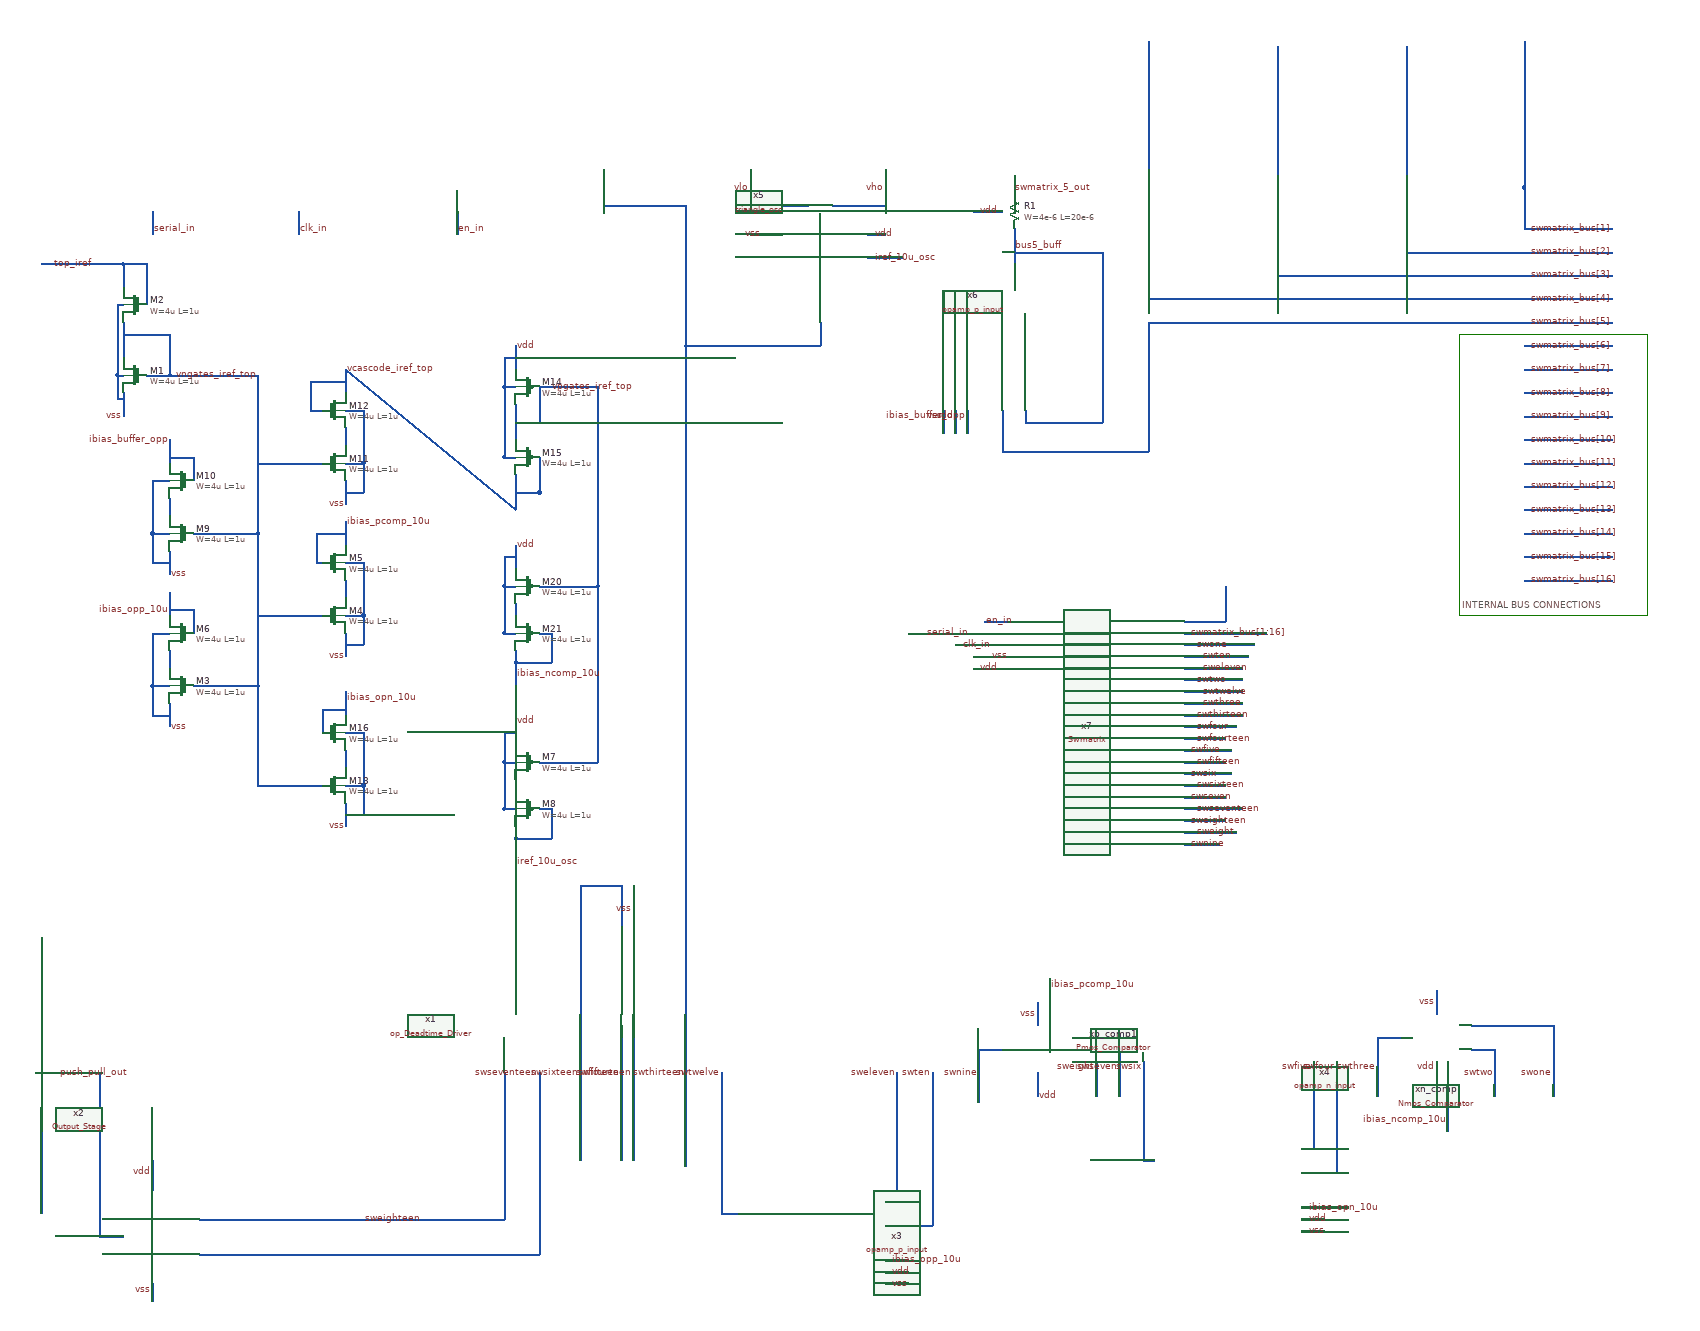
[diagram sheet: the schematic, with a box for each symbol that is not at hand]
v {xschem version=3.4.7 file_version=1.2}
G {}
K {}
V {}
S {}
E {}
L 4 2880 -2580 3160 -2580 {}
L 4 2880 -2580 2880 -2100 {}
L 4 2880 -2100 3200 -2100 {}
L 4 3200 -2580 3200 -2100 {}
L 4 3160 -2580 3200 -2580 {}
T {INTERNAL BUS CONNECTIONS} 2885 -2130 0 0 0.4 0.4 {}
N 1850 -2800 1900 -2800 {lab=vho}
N 1900 -2860 1900 -2800 {lab=vho}
N 1670 -2860 1670 -2800 {lab=vlo}
N 460 -1550 460 -1320 {lab=push_pull_out}
N 460 -1320 460 -1080 {lab=push_pull_out}
N 460 -2700 490 -2700 {lab=top_iref}
N 1420 -2860 1420 -2840 {lab=swmatrix_pin[13]}
N 2990 -3080 2990 -3060 {lab=swmatrix_bus[1]}
N 2570 -3070 2570 -3050 {lab=swmatrix_bus[3]}
N 2350 -3080 2350 -3060 {lab=swmatrix_bus[4]}
N 2790 -3070 2790 -3050 {lab=swmatrix_bus[2]}
N 2120 -2850 2120 -2830 {lab=swmatrix_5_out}
N 2570 -2850 2570 -2820 {lab=swmatrix_bus[3]}
N 2790 -2850 2790 -2820 {lab=swmatrix_bus[2]}
N 2990 -2860 2990 -2830 {lab=swmatrix_bus[1]}
N 2120 -2750 2120 -2700 {lab=bus5_buff}
N 2140 -2450 2140 -2430 {lab=bus5_buff}
N 2140 -2430 2270 -2430 {lab=bus5_buff}
N 2270 -2710 2270 -2430 {lab=bus5_buff}
N 2120 -2720 2270 -2720 {lab=bus5_buff}
N 2270 -2720 2270 -2710 {lab=bus5_buff}
N 650 -1170 650 -1120 {lab=vdd}
N 650 -2790 650 -2750 {lab=serial_in}
N 900 -2790 900 -2750 {lab=clk_in}
N 1170 -2790 1170 -2750 {lab=en_in}
N 1670 -2750 1710 -2750 {lab=vss}
N 1870 -2750 1900 -2750 {lab=vdd}
N 1880 -2710 1930 -2710 {lab=iref_10u_osc}
N 1870 -2710 1880 -2710 {lab=iref_10u_osc}
N 1790 -2600 1790 -2560 {lab=swmatrix_pin[13]}
N 2000 -2450 2000 -2410 {lab=vss}
N 2020 -2450 2020 -2410 {lab=vdd}
N 2040 -2450 2040 -2410 {lab=ibias_buffer_opp}
N 2100 -2450 2100 -2390 {lab=swmatrix_bus[5]}
N 1900 -960 1940 -960 {lab=vss}
N 1900 -980 1940 -980 {lab=vdd}
N 1900 -1000 1940 -1000 {lab=ibias_opp_10u}
N 2610 -1050 2650 -1050 {lab=vss}
N 2610 -1070 2650 -1070 {lab=vdd}
N 2610 -1090 2650 -1090 {lab=ibias_opn_10u}
N 1900 -1100 1920 -1100 {lab=swmatrix_pin[11]}
N 1920 -1220 1920 -1100 {lab=swmatrix_pin[11]}
N 1980 -1320 1980 -1060 {lab=swmatrix_pin[10]}
N 1920 -1320 1920 -1220 {lab=swmatrix_pin[11]}
N 1620 -1320 1620 -1080 {lab=swmatrix_pin[12]}
N 2610 -1190 2630 -1190 {lab=swmatrix_pin[5]}
N 2630 -1310 2630 -1190 {lab=swmatrix_pin[5]}
N 2610 -1150 2650 -1150 {lab=swmatrix_pin[4]}
N 2650 -1090 2690 -1090 {lab=ibias_opn_10u}
N 2160 -1440 2160 -1400 {lab=vss}
N 2160 -1320 2160 -1280 {lab=vdd}
N 2160 -1440 2160 -1400 {lab=vss}
N 2160 -1320 2160 -1280 {lab=vdd}
N 2180 -1440 2180 -1400 {lab=ibias_pcomp_10u}
N 2180 -1480 2180 -1440 {lab=ibias_pcomp_10u}
N 2060 -1360 2100 -1360 {lab=swmatrix_pin[9]}
N 2220 -1340 2260 -1340 {lab=swmatrix_pin[8]}
N 2900 -1360 2940 -1360 {lab=swmatrix_pin[2]}
N 2900 -1400 3040 -1400 {lab=swmatrix_pin[1]}
N 2740 -1380 2780 -1380 {lab=swmatrix_pin[3]}
N 2840 -1460 2840 -1420 {lab=vss}
N 2840 -1460 2840 -1420 {lab=vss}
N 2860 -1340 2860 -1300 {lab=ibias_ncomp_10u}
N 1470 -1640 1470 -1570 {lab=vss}
N 1450 -1640 1450 -1570 {lab=swmatrix_pin[16]}
N 1380 -1640 1380 -1300 {lab=swmatrix_pin[16]}
N 1450 -1400 1450 -1300 {lab=swmatrix_pin[15]}
N 1670 -2800 1770 -2800 {lab=vlo}
N 1810 -2800 1850 -2800 {lab=vho}
N 1450 -1300 1450 -1170 {lab=swmatrix_pin[15]}
N 1380 -1300 1380 -1170 {lab=swmatrix_pin[16]}
N 1470 -1400 1470 -1170 {lab=swmatrix_pin[14]}
N 650 -960 650 -930 {lab=vss}
N 730 -1070 1250 -1070 {lab=swmatrix_pin[18]}
N 1250 -1170 1250 -1070 {lab=swmatrix_pin[18]}
N 730 -1010 1310 -1010 {lab=swmatrix_pin[17]}
N 1310 -1160 1310 -1010 {lab=swmatrix_pin[17]}
N 1310 -1170 1310 -1160 {lab=swmatrix_pin[17]}
N 1250 -1320 1250 -1170 {lab=swmatrix_pin[18]}
N 1310 -1320 1310 -1170 {lab=swmatrix_pin[17]}
N 2060 -1360 2060 -1300 {lab=swmatrix_pin[9]}
N 2260 -1340 2260 -1280 {lab=swmatrix_pin[8]}
N 2300 -1380 2300 -1280 {lab=swmatrix_pin[7]}
N 2740 -1380 2740 -1280 {lab=swmatrix_pin[3]}
N 2940 -1360 2940 -1280 {lab=swmatrix_pin[2]}
N 3040 -1400 3040 -1280 {lab=swmatrix_pin[1]}
N 2860 -1300 2860 -1220 {lab=ibias_ncomp_10u}
N 2670 -1310 2670 -1150 {lab=swmatrix_pin[4]}
N 2340 -1340 2340 -1170 {lab=swmatrix_pin[6]}
N 2630 -1340 2630 -1310 {lab=swmatrix_pin[5]}
N 2670 -1340 2670 -1310 {lab=swmatrix_pin[4]}
N 2840 -1340 2840 -1310 {lab=vdd}
N 1560 -2280 1560 -1160 {lab=swmatrix_pin[13]}
N 1380 -1640 1450 -1640 {lab=swmatrix_pin[16]}
N 1620 -1080 1650 -1080 {lab=swmatrix_pin[12]}
N 1900 -1060 1980 -1060 {lab=swmatrix_pin[10]}
N 2060 -1300 2060 -1270 {lab=swmatrix_pin[9]}
N 2650 -1150 2670 -1150 {lab=swmatrix_pin[4]}
N 2340 -1170 2360 -1170 {lab=swmatrix_pin[6]}
N 2220 -1380 2300 -1380 {lab=swmatrix_pin[7]}
N 2990 -2830 2990 -2820 {lab=swmatrix_bus[1]}
N 2120 -2760 2120 -2750 {lab=bus5_buff}
N 2120 -2830 2120 -2820 {lab=swmatrix_5_out}
N 2050 -2790 2100 -2790 {lab=vdd}
N 2990 -2820 2990 -2760 {lab=swmatrix_bus[1]}
N 2990 -2760 3140 -2760 {lab=swmatrix_bus[1]}
N 2790 -2720 3140 -2720 {lab=swmatrix_bus[2]}
N 2790 -2820 2790 -2720 {lab=swmatrix_bus[2]}
N 2570 -2820 2570 -2680 {lab=swmatrix_bus[3]}
N 2570 -2680 3140 -2680 {lab=swmatrix_bus[3]}
N 2350 -2640 3140 -2640 {lab=swmatrix_bus[4]}
N 2990 -2600 3140 -2600 {lab=swmatrix_bus[5]}
N 2990 -2560 3140 -2560 {lab=swmatrix_bus[6]}
N 2990 -2520 3140 -2520 {lab=swmatrix_bus[7]}
N 2990 -2480 3140 -2480 {lab=swmatrix_bus[8]}
N 2990 -2440 3140 -2440 {lab=swmatrix_bus[9]}
N 2990 -2400 3140 -2400 {lab=swmatrix_bus[10]}
N 2990 -2360 3140 -2360 {lab=swmatrix_bus[11]}
N 2990 -2320 3140 -2320 {lab=swmatrix_bus[12]}
N 2560 -2600 2990 -2600 {lab=swmatrix_bus[5]}
N 2350 -2600 2560 -2600 {lab=swmatrix_bus[5]}
N 2350 -2600 2350 -2380 {lab=swmatrix_bus[5]}
N 2100 -2380 2350 -2380 {lab=swmatrix_bus[5]}
N 2100 -2390 2100 -2380 {lab=swmatrix_bus[5]}
N 2990 -2280 3140 -2280 {lab=swmatrix_bus[13]}
N 2990 -2240 3140 -2240 {lab=swmatrix_bus[14]}
N 2990 -2200 3140 -2200 {lab=swmatrix_bus[15]}
N 2990 -2160 3140 -2160 {lab=swmatrix_bus[16]}
N 490 -2700 600 -2700 {lab=top_iref}
N 590 -2510 600 -2510 {lab=vss}
N 600 -2480 600 -2450 {lab=vss}
N 590 -2510 590 -2470 {lab=vss}
N 590 -2470 600 -2470 {lab=vss}
N 600 -2450 600 -2440 {lab=vss}
N 640 -2510 680 -2510 {lab=vngates_iref_top}
N 600 -2580 680 -2580 {lab=vngates_iref_top}
N 600 -2600 600 -2540 {lab=vngates_iref_top}
N 590 -2630 600 -2630 {lab=vss}
N 590 -2630 590 -2510 {lab=vss}
N 600 -2700 600 -2660 {lab=top_iref}
N 640 -2700 640 -2630 {lab=top_iref}
N 600 -2700 640 -2700 {lab=top_iref}
N 980 -2070 980 -2030 {lab=vss}
N 980 -2100 1010 -2100 {lab=vss}
N 1010 -2100 1010 -2050 {lab=vss}
N 980 -2050 1010 -2050 {lab=vss}
N 980 -2160 980 -2130 {lab=#net1}
N 900 -2100 940 -2100 {lab=vngates_iref_top}
N 980 -2260 980 -2220 {lab=ibias_pcomp_10u}
N 990 -2190 1010 -2190 {lab=vss}
N 1010 -2190 1010 -2100 {lab=vss}
N 980 -2190 990 -2190 {lab=vss}
N 680 -1950 680 -1910 {lab=vss}
N 650 -1980 680 -1980 {lab=vss}
N 650 -1980 650 -1930 {lab=vss}
N 650 -1930 680 -1930 {lab=vss}
N 680 -2040 680 -2010 {lab=#net2}
N 720 -1980 760 -1980 {lab=vngates_iref_top}
N 680 -2140 680 -2100 {lab=ibias_opp_10u}
N 650 -2070 670 -2070 {lab=vss}
N 650 -2070 650 -1980 {lab=vss}
N 670 -2070 680 -2070 {lab=vss}
N 680 -2210 680 -2170 {lab=vss}
N 650 -2240 680 -2240 {lab=vss}
N 650 -2240 650 -2190 {lab=vss}
N 650 -2190 680 -2190 {lab=vss}
N 680 -2300 680 -2270 {lab=#net3}
N 790 -2240 830 -2240 {lab=vngates_iref_top}
N 650 -2330 670 -2330 {lab=vss}
N 650 -2330 650 -2240 {lab=vss}
N 670 -2330 680 -2330 {lab=vss}
N 680 -2400 680 -2360 {lab=ibias_buffer_opp}
N 830 -2510 830 -2240 {lab=vngates_iref_top}
N 1560 -2560 1560 -2280 {lab=swmatrix_pin[13]}
N 560 -1040 600 -1040 {lab=push_pull_out}
N 560 -1320 560 -1040 {lab=push_pull_out}
N 450 -1320 560 -1320 {lab=push_pull_out}
N 830 -2240 830 -1980 {lab=vngates_iref_top}
N 980 -2330 980 -2290 {lab=vss}
N 980 -2360 1010 -2360 {lab=vss}
N 1010 -2360 1010 -2310 {lab=vss}
N 980 -2310 1010 -2310 {lab=vss}
N 980 -2420 980 -2390 {lab=#net4}
N 900 -2360 940 -2360 {lab=vngates_iref_top}
N 990 -2450 1010 -2450 {lab=vss}
N 1010 -2450 1010 -2360 {lab=vss}
N 980 -2450 990 -2450 {lab=vss}
N 980 -2520 980 -2470 {lab=vcascode_iref_top}
N 1270 -2310 1310 -2310 {lab=vcascode_iref_top}
N 1310 -2370 1310 -2310 {lab=vcascode_iref_top}
N 1250 -2370 1270 -2370 {lab=vdd}
N 1270 -2430 1310 -2430 {lab=vpgates_iref_top}
N 1310 -2490 1310 -2430 {lab=vpgates_iref_top}
N 1250 -2490 1270 -2490 {lab=vdd}
N 1250 -2540 1250 -2490 {lab=vdd}
N 1250 -2540 1260 -2540 {lab=vdd}
N 1260 -2540 1270 -2540 {lab=vdd}
N 1270 -2560 1270 -2520 {lab=vdd}
N 1270 -2460 1270 -2400 {lab=vpgates_iref_top}
N 1250 -2490 1250 -2420 {lab=vdd}
N 1310 -2490 1410 -2490 {lab=vpgates_iref_top}
N 1270 -2340 1270 -2280 {lab=vcascode_iref_top}
N 1270 -2310 1310 -2310 {lab=vcascode_iref_top}
N 1310 -2370 1310 -2310 {lab=vcascode_iref_top}
N 1250 -2370 1270 -2370 {lab=vdd}
N 1250 -2420 1250 -2370 {lab=vdd}
N 1270 -2460 1270 -2400 {lab=vpgates_iref_top}
N 1410 -2490 1410 -2150 {lab=vpgates_iref_top}
N 1250 -2070 1270 -2070 {lab=vdd}
N 1250 -2150 1270 -2150 {lab=vdd}
N 1250 -2200 1250 -2150 {lab=vdd}
N 1250 -2200 1260 -2200 {lab=vdd}
N 1260 -2200 1270 -2200 {lab=vdd}
N 1270 -2220 1270 -2180 {lab=vdd}
N 1310 -2150 1410 -2150 {lab=vpgates_iref_top}
N 1250 -2070 1270 -2070 {lab=vdd}
N 1270 -2120 1270 -2110 {lab=#net5}
N 1270 -2110 1270 -2100 {lab=#net5}
N 1250 -2150 1250 -2070 {lab=vdd}
N 1310 -2070 1330 -2070 {lab=ibias_ncomp_10u}
N 1330 -2070 1330 -2020 {lab=ibias_ncomp_10u}
N 1270 -2020 1330 -2020 {lab=ibias_ncomp_10u}
N 1270 -2040 1270 -2020 {lab=ibias_ncomp_10u}
N 1270 -2020 1270 -1980 {lab=ibias_ncomp_10u}
N 920 -2450 940 -2450 {lab=vcascode_iref_top}
N 920 -2500 920 -2450 {lab=vcascode_iref_top}
N 920 -2500 980 -2500 {lab=vcascode_iref_top}
N 930 -2190 940 -2190 {lab=ibias_pcomp_10u}
N 930 -2240 930 -2190 {lab=ibias_pcomp_10u}
N 930 -2240 980 -2240 {lab=ibias_pcomp_10u}
N 720 -2370 720 -2330 {lab=ibias_buffer_opp}
N 680 -2370 720 -2370 {lab=ibias_buffer_opp}
N 720 -2110 720 -2070 {lab=ibias_opp_10u}
N 680 -2110 720 -2110 {lab=ibias_opp_10u}
N 1560 -2560 1790 -2560 {lab=swmatrix_pin[13]}
N 1560 -2800 1560 -2560 {lab=swmatrix_pin[13]}
N 1420 -2800 1550 -2800 {lab=swmatrix_pin[13]}
N 1420 -2840 1420 -2800 {lab=swmatrix_pin[13]}
N 1550 -2800 1560 -2800 {lab=swmatrix_pin[13]}
N 680 -2580 680 -2510 {lab=vngates_iref_top}
N 680 -2510 760 -2510 {lab=vngates_iref_top}
N 780 -2240 790 -2240 {lab=vngates_iref_top}
N 720 -2240 780 -2240 {lab=vngates_iref_top}
N 760 -1980 830 -1980 {lab=vngates_iref_top}
N 830 -1980 830 -1840 {lab=vngates_iref_top}
N 830 -2100 900 -2100 {lab=vngates_iref_top}
N 830 -2360 900 -2360 {lab=vngates_iref_top}
N 760 -2510 830 -2510 {lab=vngates_iref_top}
N 980 -1780 980 -1740 {lab=vss}
N 980 -1810 1010 -1810 {lab=vss}
N 1010 -1810 1010 -1760 {lab=vss}
N 980 -1760 1010 -1760 {lab=vss}
N 980 -1870 980 -1840 {lab=#net6}
N 900 -1810 940 -1810 {lab=vngates_iref_top}
N 980 -1970 980 -1930 {lab=ibias_opn_10u}
N 990 -1900 1010 -1900 {lab=vss}
N 1010 -1900 1010 -1810 {lab=vss}
N 980 -1900 990 -1900 {lab=vss}
N 940 -1940 940 -1900 {lab=ibias_opn_10u}
N 940 -1940 980 -1940 {lab=ibias_opn_10u}
N 830 -1810 900 -1810 {lab=vngates_iref_top}
N 830 -1830 830 -1810 {lab=vngates_iref_top}
N 830 -1840 830 -1830 {lab=vngates_iref_top}
N 1250 -1770 1270 -1770 {lab=vdd}
N 1250 -1850 1270 -1850 {lab=vdd}
N 1250 -1900 1250 -1850 {lab=vdd}
N 1250 -1900 1260 -1900 {lab=vdd}
N 1260 -1900 1270 -1900 {lab=vdd}
N 1270 -1920 1270 -1880 {lab=vdd}
N 1310 -1850 1410 -1850 {lab=vpgates_iref_top}
N 1250 -1770 1270 -1770 {lab=vdd}
N 1270 -1820 1270 -1810 {lab=#net7}
N 1270 -1810 1270 -1800 {lab=#net7}
N 1250 -1850 1250 -1770 {lab=vdd}
N 1310 -1770 1330 -1770 {lab=iref_10u_osc}
N 1330 -1770 1330 -1720 {lab=iref_10u_osc}
N 1270 -1720 1330 -1720 {lab=iref_10u_osc}
N 1270 -1740 1270 -1720 {lab=iref_10u_osc}
N 1270 -1720 1270 -1680 {lab=iref_10u_osc}
N 1410 -2150 1410 -1850 {lab=vpgates_iref_top}
N 980 -2520 1270 -2280 {lab=vcascode_iref_top}
N 2350 -2860 2350 -2640 {lab=swmatrix_bus[4]}
N 2410 -2070 2550 -2070 {lab=swmatrix_bus[1:16]}
N 2410 -2090 2480 -2090 {lab=#net8}
N 2480 -2150 2480 -2090 {lab=#net8}
N 2050 -2050 2110 -2050 {lab=clk_in}
N 2070 -2090 2110 -2090 {lab=en_in}
N 2020 -2050 2050 -2050 {lab=clk_in}
N 2050 -2030 2110 -2030 {lab=vss}
N 2050 -2010 2110 -2010 {lab=vdd}
N 1940 -2070 2110 -2070 {lab=serial_in}
N 2350 -3060 2350 -2840 {lab=swmatrix_bus[4]}
N 2570 -3050 2570 -2840 {lab=swmatrix_bus[3]}
N 2790 -3050 2790 -2840 {lab=swmatrix_bus[2]}
N 2990 -3060 2990 -2830 {lab=swmatrix_bus[1]}
N 2410 -2050 2530 -2050 {lab=swone}
N 2410 -2030 2520 -2030 {lab=swten}
N 2410 -2010 2510 -2010 {lab=sweleven}
N 2410 -1990 2510 -1990 {lab=swtwo}
N 2410 -1970 2510 -1970 {lab=swtwelve}
N 2410 -1950 2510 -1950 {lab=swthree}
N 2410 -1930 2510 -1930 {lab=swthirteen}
N 2410 -1910 2500 -1910 {lab=swfour}
N 2410 -1890 2480 -1890 {lab=swfourteen}
N 2410 -1870 2490 -1870 {lab=swfive}
N 2410 -1850 2480 -1850 {lab=#net9}
N 2410 -1810 2480 -1810 {lab=#net10}
N 2410 -1830 2490 -1830 {lab=#net11}
N 2410 -1790 2480 -1790 {lab=#net12}
N 2410 -1770 2510 -1770 {lab=#net13}
N 2410 -1750 2480 -1750 {lab=#net14}
N 2410 -1730 2500 -1730 {lab=#net15}
N 2410 -1710 2470 -1710 {lab=#net16}
C {title.sym} 70 30 0 0 {name=l1 author=", X.J. Lee, Christopher O Amankwaa"}
C {libs/core_analog/Comparator/Nmos_Comparator.sym} 2880 -1340 2 0 {name=xn_comp}
C {libs/core_analog/op_Deadtime_Driver/op_Deadtime_Driver.sym} 1460 -1420 3 1 {name=x1}
C {libs/core_analog/Output_Stage/Output_Stage.sym} 680 -1040 0 1 {name=x2}
C {libs/core_analog/opamp/opamp_p_input.sym} 1880 -1170 0 1 {name=x3}
C {libs/core_analog/opamp/opamp_n_input.sym} 2590 -1260 0 1 {name=x4}
C {libs/core_analog/oscillator/triangle_osc.sym} 1850 -2780 1 0 {name=x5}
C {libs/core_analog/opamp/opamp_p_input.sym} 2210 -2470 1 1 {name=x6}
C {lab_wire.sym} 1900 -2830 0 0 {name=p5 sig_type=std_logic lab=vho}
C {lab_wire.sym} 1670 -2830 0 0 {name=p6 sig_type=std_logic lab=vlo}
C {lab_wire.sym} 490 -1320 0 1 {name=p13 sig_type=std_logic lab=push_pull_out}
C {lab_wire.sym} 480 -2700 2 0 {name=p33 sig_type=std_logic lab=top_iref}
C {noconn.sym} 2570 -3070 1 0 {name=l19}
C {lab_wire.sym} 3000 -2640 0 1 {name=p56 sig_type=std_logic lab=swmatrix_bus[4]}
C {noconn.sym} 2790 -3070 3 1 {name=l21}
C {lab_wire.sym} 3000 -2600 0 1 {name=p59 sig_type=std_logic lab=swmatrix_bus[5]}
C {lab_wire.sym} 3000 -2680 0 1 {name=p60 sig_type=std_logic lab=swmatrix_bus[3]}
C {lab_wire.sym} 3000 -2720 0 1 {name=p61 sig_type=std_logic lab=swmatrix_bus[2]}
C {lab_wire.sym} 3000 -2760 0 1 {name=p62 sig_type=std_logic lab=swmatrix_bus[1]}
C {noconn.sym} 2990 -3080 3 1 {name=l22}
C {noconn.sym} 2350 -3080 3 1 {name=l23}
C {lab_wire.sym} 650 -1150 0 0 {name=p47 sig_type=std_logic lab=vdd}
C {lab_wire.sym} 650 -2760 0 1 {name=p35 sig_type=std_logic lab=serial_in
}
C {lab_wire.sym} 900 -2760 0 1 {name=p40 sig_type=std_logic lab=clk_in
}
C {lab_wire.sym} 1170 -2760 0 1 {name=p63 sig_type=std_logic lab=en_in}
C {lab_wire.sym} 1690 -2750 0 0 {name=p64 sig_type=std_logic lab=vss}
C {lab_wire.sym} 1880 -2750 0 1 {name=p65 sig_type=std_logic lab=vdd}
C {lab_wire.sym} 1880 -2710 0 1 {name=p66 sig_type=std_logic lab=iref_10u_osc}
C {lab_wire.sym} 2020 -2440 3 0 {name=p67 sig_type=std_logic lab=vdd}
C {lab_wire.sym} 2000 -2440 3 0 {name=p68 sig_type=std_logic lab=vss}
C {lab_wire.sym} 1910 -980 2 0 {name=p70 sig_type=std_logic lab=vdd}
C {lab_wire.sym} 1910 -960 2 0 {name=p71 sig_type=std_logic lab=vss}
C {lab_wire.sym} 1910 -1000 0 1 {name=p72 sig_type=std_logic lab=ibias_opp_10u}
C {lab_wire.sym} 2620 -1070 2 0 {name=p73 sig_type=std_logic lab=vdd}
C {lab_wire.sym} 2620 -1050 2 0 {name=p74 sig_type=std_logic lab=vss}
C {lab_wire.sym} 2620 -1090 0 1 {name=p75 sig_type=std_logic lab=ibias_opn_10u}
C {lab_wire.sym} 2160 -1280 0 1 {name=p76 sig_type=std_logic lab=vdd}
C {lab_wire.sym} 2180 -1470 2 0 {name=p78 sig_type=std_logic lab=ibias_pcomp_10u}
C {libs/core_analog/Comparator/Pmos_Comparator.sym} 2200 -1320 2 0 {name=xp_comp1}
C {lab_wire.sym} 2160 -1420 0 0 {name=p80 sig_type=std_logic lab=vss}
C {lab_wire.sym} 2840 -1440 0 0 {name=p82 sig_type=std_logic lab=vss}
C {lab_wire.sym} 2840 -1330 2 1 {name=p83 sig_type=std_logic lab=vdd}
C {lab_wire.sym} 2860 -1240 2 1 {name=p85 sig_type=std_logic lab=ibias_ncomp_10u}
C {lab_wire.sym} 1470 -1600 1 0 {name=p86 sig_type=std_logic lab=vss}
C {lab_wire.sym} 2630 -1330 1 1 {name=p94 sig_type=std_logic lab=swfive}
C {lab_wire.sym} 3040 -1320 1 1 {name=p101 sig_type=std_logic lab=swone
}
C {lab_wire.sym} 650 -950 3 0 {name=p102 sig_type=std_logic lab=vss}
C {lab_wire.sym} 2120 -2730 0 1 {name=p77 sig_type=std_logic lab=bus5_buff}
C {symbols/ppolyf_s.sym} 2120 -2790 0 0 {name=R1
W=4e-6
L=20e-6
model=ppolyf_s
spiceprefix=X
m=1}
C {lab_wire.sym} 2060 -2790 0 1 {name=p79 sig_type=std_logic lab=vdd}
C {lab_wire.sym} 3000 -2560 0 1 {name=p81 sig_type=std_logic lab=swmatrix_bus[6]}
C {lab_wire.sym} 3000 -2400 0 1 {name=p84 sig_type=std_logic lab=swmatrix_bus[10]}
C {lab_wire.sym} 3000 -2360 0 1 {name=p105 sig_type=std_logic lab=swmatrix_bus[11]}
C {lab_wire.sym} 3000 -2440 0 1 {name=p106 sig_type=std_logic lab=swmatrix_bus[9]}
C {lab_wire.sym} 3000 -2480 0 1 {name=p107 sig_type=std_logic lab=swmatrix_bus[8]}
C {lab_wire.sym} 3000 -2520 0 1 {name=p108 sig_type=std_logic lab=swmatrix_bus[7]}
C {lab_wire.sym} 3000 -2320 0 1 {name=p109 sig_type=std_logic lab=swmatrix_bus[12]}
C {lab_wire.sym} 3000 -2240 0 1 {name=p110 sig_type=std_logic lab=swmatrix_bus[14]}
C {lab_wire.sym} 3000 -2200 0 1 {name=p111 sig_type=std_logic lab=swmatrix_bus[15]}
C {lab_wire.sym} 3000 -2280 0 1 {name=p112 sig_type=std_logic lab=swmatrix_bus[13]}
C {lab_wire.sym} 3000 -2160 0 1 {name=p113 sig_type=std_logic lab=swmatrix_bus[16]}
C {symbols/nfet_03v3.sym} 620 -2510 0 1 {name=M1
L=1u
W=4u
nf=1
m=1
ad="'int((nf+1)/2) * W/nf * 0.18u'"
pd="'2*int((nf+1)/2) * (W/nf + 0.18u)'"
as="'int((nf+2)/2) * W/nf * 0.18u'"
ps="'2*int((nf+2)/2) * (W/nf + 0.18u)'"
nrd="'0.18u / W'" nrs="'0.18u / W'"
sa=0 sb=0 sd=0
model=nfet_03v3
spiceprefix=X
}
C {lab_wire.sym} 600 -2440 0 0 {name=p114 sig_type=std_logic lab=vss}
C {symbols/nfet_03v3.sym} 620 -2630 0 1 {name=M2
L=1u
W=4u
nf=1
m=1
ad="'int((nf+1)/2) * W/nf * 0.18u'"
pd="'2*int((nf+1)/2) * (W/nf + 0.18u)'"
as="'int((nf+2)/2) * W/nf * 0.18u'"
ps="'2*int((nf+2)/2) * (W/nf + 0.18u)'"
nrd="'0.18u / W'" nrs="'0.18u / W'"
sa=0 sb=0 sd=0
model=nfet_03v3
spiceprefix=X
}
C {lab_wire.sym} 830 -2510 0 0 {name=p116 sig_type=std_logic lab=vngates_iref_top}
C {lab_wire.sym} 980 -2260 2 0 {name=p117 sig_type=std_logic lab=ibias_pcomp_10u}
C {symbols/nfet_03v3.sym} 960 -2100 0 0 {name=M4
L=1u
W=4u
nf=1
m=1
ad="'int((nf+1)/2) * W/nf * 0.18u'"
pd="'2*int((nf+1)/2) * (W/nf + 0.18u)'"
as="'int((nf+2)/2) * W/nf * 0.18u'"
ps="'2*int((nf+2)/2) * (W/nf + 0.18u)'"
nrd="'0.18u / W'" nrs="'0.18u / W'"
sa=0 sb=0 sd=0
model=nfet_03v3
spiceprefix=X
}
C {lab_wire.sym} 980 -2030 0 0 {name=p118 sig_type=std_logic lab=vss}
C {symbols/nfet_03v3.sym} 960 -2190 0 0 {name=M5
L=1u
W=4u
nf=1
m=1
ad="'int((nf+1)/2) * W/nf * 0.18u'"
pd="'2*int((nf+1)/2) * (W/nf + 0.18u)'"
as="'int((nf+2)/2) * W/nf * 0.18u'"
ps="'2*int((nf+2)/2) * (W/nf + 0.18u)'"
nrd="'0.18u / W'" nrs="'0.18u / W'"
sa=0 sb=0 sd=0
model=nfet_03v3
spiceprefix=X
}
C {symbols/nfet_03v3.sym} 700 -1980 0 1 {name=M3
L=1u
W=4u
nf=1
m=1
ad="'int((nf+1)/2) * W/nf * 0.18u'"
pd="'2*int((nf+1)/2) * (W/nf + 0.18u)'"
as="'int((nf+2)/2) * W/nf * 0.18u'"
ps="'2*int((nf+2)/2) * (W/nf + 0.18u)'"
nrd="'0.18u / W'" nrs="'0.18u / W'"
sa=0 sb=0 sd=0
model=nfet_03v3
spiceprefix=X
}
C {lab_wire.sym} 680 -1910 0 1 {name=p115 sig_type=std_logic lab=vss}
C {symbols/nfet_03v3.sym} 700 -2070 0 1 {name=M6
L=1u
W=4u
nf=1
m=1
ad="'int((nf+1)/2) * W/nf * 0.18u'"
pd="'2*int((nf+1)/2) * (W/nf + 0.18u)'"
as="'int((nf+2)/2) * W/nf * 0.18u'"
ps="'2*int((nf+2)/2) * (W/nf + 0.18u)'"
nrd="'0.18u / W'" nrs="'0.18u / W'"
sa=0 sb=0 sd=0
model=nfet_03v3
spiceprefix=X
}
C {lab_wire.sym} 680 -2110 0 0 {name=p30 sig_type=std_logic lab=ibias_opp_10u}
C {lab_wire.sym} 2040 -2440 3 0 {name=p119 sig_type=std_logic lab=ibias_buffer_opp}
C {lab_wire.sym} 680 -2400 2 1 {name=p122 sig_type=std_logic lab=ibias_buffer_opp}
C {symbols/nfet_03v3.sym} 700 -2240 0 1 {name=M9
L=1u
W=4u
nf=1
m=1
ad="'int((nf+1)/2) * W/nf * 0.18u'"
pd="'2*int((nf+1)/2) * (W/nf + 0.18u)'"
as="'int((nf+2)/2) * W/nf * 0.18u'"
ps="'2*int((nf+2)/2) * (W/nf + 0.18u)'"
nrd="'0.18u / W'" nrs="'0.18u / W'"
sa=0 sb=0 sd=0
model=nfet_03v3
spiceprefix=X
}
C {lab_wire.sym} 680 -2170 0 1 {name=p123 sig_type=std_logic lab=vss}
C {symbols/nfet_03v3.sym} 700 -2330 0 1 {name=M10
L=1u
W=4u
nf=1
m=1
ad="'int((nf+1)/2) * W/nf * 0.18u'"
pd="'2*int((nf+1)/2) * (W/nf + 0.18u)'"
as="'int((nf+2)/2) * W/nf * 0.18u'"
ps="'2*int((nf+2)/2) * (W/nf + 0.18u)'"
nrd="'0.18u / W'" nrs="'0.18u / W'"
sa=0 sb=0 sd=0
model=nfet_03v3
spiceprefix=X
}
C {symbols/nfet_03v3.sym} 960 -2360 0 0 {name=M11
L=1u
W=4u
nf=1
m=1
ad="'int((nf+1)/2) * W/nf * 0.18u'"
pd="'2*int((nf+1)/2) * (W/nf + 0.18u)'"
as="'int((nf+2)/2) * W/nf * 0.18u'"
ps="'2*int((nf+2)/2) * (W/nf + 0.18u)'"
nrd="'0.18u / W'" nrs="'0.18u / W'"
sa=0 sb=0 sd=0
model=nfet_03v3
spiceprefix=X
}
C {symbols/nfet_03v3.sym} 960 -2450 0 0 {name=M12
L=1u
W=4u
nf=1
m=1
ad="'int((nf+1)/2) * W/nf * 0.18u'"
pd="'2*int((nf+1)/2) * (W/nf + 0.18u)'"
as="'int((nf+2)/2) * W/nf * 0.18u'"
ps="'2*int((nf+2)/2) * (W/nf + 0.18u)'"
nrd="'0.18u / W'" nrs="'0.18u / W'"
sa=0 sb=0 sd=0
model=nfet_03v3
spiceprefix=X
}
C {lab_wire.sym} 980 -2290 0 0 {name=p124 sig_type=std_logic lab=vss}
C {lab_wire.sym} 1270 -2560 0 1 {name=p125 sig_type=std_logic lab=vdd}
C {symbols/pfet_03v3.sym} 1290 -2490 0 1 {name=M14
L=1u
W=4u
nf=1
m=1
ad="'int((nf+1)/2) * W/nf * 0.18u'"
pd="'2*int((nf+1)/2) * (W/nf + 0.18u)'"
as="'int((nf+2)/2) * W/nf * 0.18u'"
ps="'2*int((nf+2)/2) * (W/nf + 0.18u)'"
nrd="'0.18u / W'" nrs="'0.18u / W'"
sa=0 sb=0 sd=0
model=pfet_03v3
spiceprefix=X
}
C {lab_wire.sym} 980 -2520 0 1 {name=p126 sig_type=std_logic lab=vcascode_iref_top}
C {lab_wire.sym} 1330 -2490 0 1 {name=p127 sig_type=std_logic lab=vpgates_iref_top}
C {symbols/pfet_03v3.sym} 1290 -2370 0 1 {name=M15
L=1u
W=4u
nf=1
m=1
ad="'int((nf+1)/2) * W/nf * 0.18u'"
pd="'2*int((nf+1)/2) * (W/nf + 0.18u)'"
as="'int((nf+2)/2) * W/nf * 0.18u'"
ps="'2*int((nf+2)/2) * (W/nf + 0.18u)'"
nrd="'0.18u / W'" nrs="'0.18u / W'"
sa=0 sb=0 sd=0
model=pfet_03v3
spiceprefix=X
}
C {lab_wire.sym} 1270 -2220 0 1 {name=p129 sig_type=std_logic lab=vdd}
C {symbols/pfet_03v3.sym} 1290 -2150 0 1 {name=M20
L=1u
W=4u
nf=1
m=1
ad="'int((nf+1)/2) * W/nf * 0.18u'"
pd="'2*int((nf+1)/2) * (W/nf + 0.18u)'"
as="'int((nf+2)/2) * W/nf * 0.18u'"
ps="'2*int((nf+2)/2) * (W/nf + 0.18u)'"
nrd="'0.18u / W'" nrs="'0.18u / W'"
sa=0 sb=0 sd=0
model=pfet_03v3
spiceprefix=X
}
C {symbols/pfet_03v3.sym} 1290 -2070 0 1 {name=M21
L=1u
W=4u
nf=1
m=1
ad="'int((nf+1)/2) * W/nf * 0.18u'"
pd="'2*int((nf+1)/2) * (W/nf + 0.18u)'"
as="'int((nf+2)/2) * W/nf * 0.18u'"
ps="'2*int((nf+2)/2) * (W/nf + 0.18u)'"
nrd="'0.18u / W'" nrs="'0.18u / W'"
sa=0 sb=0 sd=0
model=pfet_03v3
spiceprefix=X
}
C {lab_wire.sym} 1270 -2000 2 0 {name=p131 sig_type=std_logic lab=ibias_ncomp_10u}
C {symbols/nfet_03v3.sym} 960 -1810 0 0 {name=M13
L=1u
W=4u
nf=1
m=1
ad="'int((nf+1)/2) * W/nf * 0.18u'"
pd="'2*int((nf+1)/2) * (W/nf + 0.18u)'"
as="'int((nf+2)/2) * W/nf * 0.18u'"
ps="'2*int((nf+2)/2) * (W/nf + 0.18u)'"
nrd="'0.18u / W'" nrs="'0.18u / W'"
sa=0 sb=0 sd=0
model=nfet_03v3
spiceprefix=X
}
C {lab_wire.sym} 980 -1740 0 0 {name=p128 sig_type=std_logic lab=vss}
C {symbols/nfet_03v3.sym} 960 -1900 0 0 {name=M16
L=1u
W=4u
nf=1
m=1
ad="'int((nf+1)/2) * W/nf * 0.18u'"
pd="'2*int((nf+1)/2) * (W/nf + 0.18u)'"
as="'int((nf+2)/2) * W/nf * 0.18u'"
ps="'2*int((nf+2)/2) * (W/nf + 0.18u)'"
nrd="'0.18u / W'" nrs="'0.18u / W'"
sa=0 sb=0 sd=0
model=nfet_03v3
spiceprefix=X
}
C {lab_wire.sym} 980 -1960 0 1 {name=p130 sig_type=std_logic lab=ibias_opn_10u}
C {lab_wire.sym} 1270 -1920 0 1 {name=p120 sig_type=std_logic lab=vdd}
C {symbols/pfet_03v3.sym} 1290 -1850 0 1 {name=M7
L=1u
W=4u
nf=1
m=1
ad="'int((nf+1)/2) * W/nf * 0.18u'"
pd="'2*int((nf+1)/2) * (W/nf + 0.18u)'"
as="'int((nf+2)/2) * W/nf * 0.18u'"
ps="'2*int((nf+2)/2) * (W/nf + 0.18u)'"
nrd="'0.18u / W'" nrs="'0.18u / W'"
sa=0 sb=0 sd=0
model=pfet_03v3
spiceprefix=X
}
C {symbols/pfet_03v3.sym} 1290 -1770 0 1 {name=M8
L=1u
W=4u
nf=1
m=1
ad="'int((nf+1)/2) * W/nf * 0.18u'"
pd="'2*int((nf+1)/2) * (W/nf + 0.18u)'"
as="'int((nf+2)/2) * W/nf * 0.18u'"
ps="'2*int((nf+2)/2) * (W/nf + 0.18u)'"
nrd="'0.18u / W'" nrs="'0.18u / W'"
sa=0 sb=0 sd=0
model=pfet_03v3
spiceprefix=X
}
C {lab_wire.sym} 1270 -1680 0 1 {name=p132 sig_type=std_logic lab=iref_10u_osc}
C {lab_wire.sym} 2940 -1320 1 1 {name=p100 sig_type=std_logic lab=swtwo
}
C {lab_wire.sym} 2740 -1330 1 1 {name=p99 sig_type=std_logic lab=swthree
}
C {lab_wire.sym} 2670 -1330 1 1 {name=p95 sig_type=std_logic lab=swfour
}
C {lab_wire.sym} 2340 -1330 1 1 {name=p93 sig_type=std_logic lab=swsix}
C {lab_wire.sym} 2300 -1330 1 1 {name=p97 sig_type=std_logic lab=swseven}
C {lab_wire.sym} 2260 -1330 1 1 {name=p98 sig_type=std_logic lab=sweight}
C {lab_wire.sym} 2060 -1320 3 0 {name=p91 sig_type=std_logic lab=swnine}
C {lab_wire.sym} 1980 -1320 1 1 {name=p92 sig_type=std_logic lab=swten}
C {lab_wire.sym} 1920 -1320 1 1 {name=p96 sig_type=std_logic lab=sweleven}
C {lab_wire.sym} 1620 -1320 1 1 {name=p45 sig_type=std_logic lab=swtwelve}
C {lab_wire.sym} 1470 -1320 1 1 {name=p87 sig_type=std_logic lab=swfourteen}
C {lab_wire.sym} 1450 -1320 3 0 {name=p88 sig_type=std_logic lab=swfifteen}
C {lab_wire.sym} 1380 -1320 3 0 {name=p89 sig_type=std_logic lab=swsixteen}
C {lab_wire.sym} 1310 -1320 1 1 {name=p90 sig_type=std_logic lab=swseventeen}
C {lab_wire.sym} 1560 -1320 3 0 {name=p104 sig_type=std_logic lab=swthirteen}
C {lab_wire.sym} 2120 -2830 0 1 {name=p121 sig_type=std_logic lab=swmatrix_5_out}
C {libs/core_swmatrix/Swmatrix.sym} 2260 -1900 0 0 {name=x7}
C {lab_wire.sym} 2420 -2070 0 1 {name=p133 sig_type=std_logic lab=swmatrix_bus[1:16]}
C {noconn.sym} 2480 -2150 1 0 {name=l16}
C {lab_wire.sym} 1970 -2070 0 1 {name=p135 sig_type=std_logic lab=serial_in
}
C {lab_wire.sym} 2070 -2090 0 1 {name=p136 sig_type=std_logic lab=en_in}
C {lab_wire.sym} 2030 -2050 0 1 {name=p137 sig_type=std_logic lab=clk_in
}
C {lab_wire.sym} 2080 -2030 0 1 {name=p138 sig_type=std_logic lab=vss}
C {lab_wire.sym} 2060 -2010 2 0 {name=p139 sig_type=std_logic lab=vdd}
C {noconn.sym} 3140 -2760 0 1 {name=l24}
C {noconn.sym} 3140 -2720 0 1 {name=l25}
C {noconn.sym} 3140 -2680 0 1 {name=l26}
C {noconn.sym} 3140 -2640 0 1 {name=l27}
C {noconn.sym} 3140 -2600 0 1 {name=l28}
C {noconn.sym} 3140 -2560 0 1 {name=l29}
C {noconn.sym} 3140 -2520 0 1 {name=l30}
C {noconn.sym} 3140 -2480 0 1 {name=l31}
C {noconn.sym} 3140 -2440 0 1 {name=l32}
C {noconn.sym} 3140 -2400 0 1 {name=l33}
C {noconn.sym} 3140 -2360 0 1 {name=l34}
C {noconn.sym} 3140 -2320 0 1 {name=l35}
C {noconn.sym} 3140 -2280 0 1 {name=l36}
C {noconn.sym} 3140 -2240 0 1 {name=l37}
C {noconn.sym} 3140 -2200 0 1 {name=l38}
C {noconn.sym} 3140 -2160 0 1 {name=l39}
C {lab_wire.sym} 2430 -2050 0 1 {name=p1 sig_type=std_logic lab=swone}
C {lab_wire.sym} 2440 -2030 0 1 {name=p2 sig_type=std_logic lab=swten}
C {lab_wire.sym} 2440 -2010 0 1 {name=p3 sig_type=std_logic lab=sweleven}
C {lab_wire.sym} 2430 -1990 0 1 {name=p4 sig_type=std_logic lab=swtwo}
C {lab_wire.sym} 2440 -1970 0 1 {name=p7 sig_type=std_logic lab=swtwelve}
C {lab_wire.sym} 2440 -1950 0 1 {name=p8 sig_type=std_logic lab=swthree}
C {lab_wire.sym} 2430 -1930 0 1 {name=p9 sig_type=std_logic lab=swthirteen}
C {lab_wire.sym} 2430 -1890 0 1 {name=p10 sig_type=std_logic lab=swfourteen}
C {lab_wire.sym} 2430 -1910 0 1 {name=p11 sig_type=std_logic lab=swfour}
C {lab_wire.sym} 2420 -1870 0 1 {name=p12 sig_type=std_logic lab=swfive}
C {lab_wire.sym} 2430 -1850 0 1 {name=p14 sig_type=std_logic lab=swfifteen}
C {lab_wire.sym} 2420 -1830 0 1 {name=p15 sig_type=std_logic lab=swsix}
C {lab_wire.sym} 2430 -1810 0 1 {name=p16 sig_type=std_logic lab=swsixteen}
C {lab_wire.sym} 2420 -1790 0 1 {name=p17 sig_type=std_logic lab=swseven}
C {lab_wire.sym} 2430 -1770 0 1 {name=p18 sig_type=std_logic lab=swseventeen}
C {lab_wire.sym} 2420 -1750 0 1 {name=p19 sig_type=std_logic lab=sweighteen}
C {lab_wire.sym} 2430 -1730 0 1 {name=p20 sig_type=std_logic lab=sweight}
C {lab_wire.sym} 2420 -1710 0 1 {name=p21 sig_type=std_logic lab=swnine}
C {lab_wire.sym} 1010 -1070 0 1 {name=p22 sig_type=std_logic lab=sweighteen}
